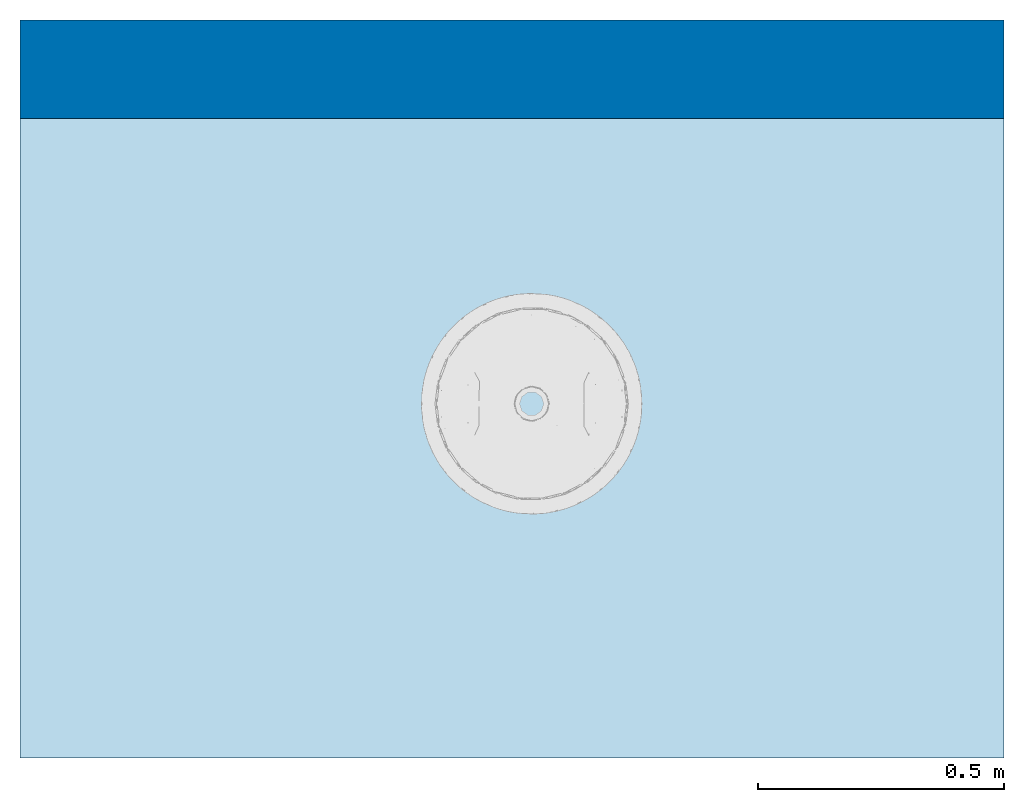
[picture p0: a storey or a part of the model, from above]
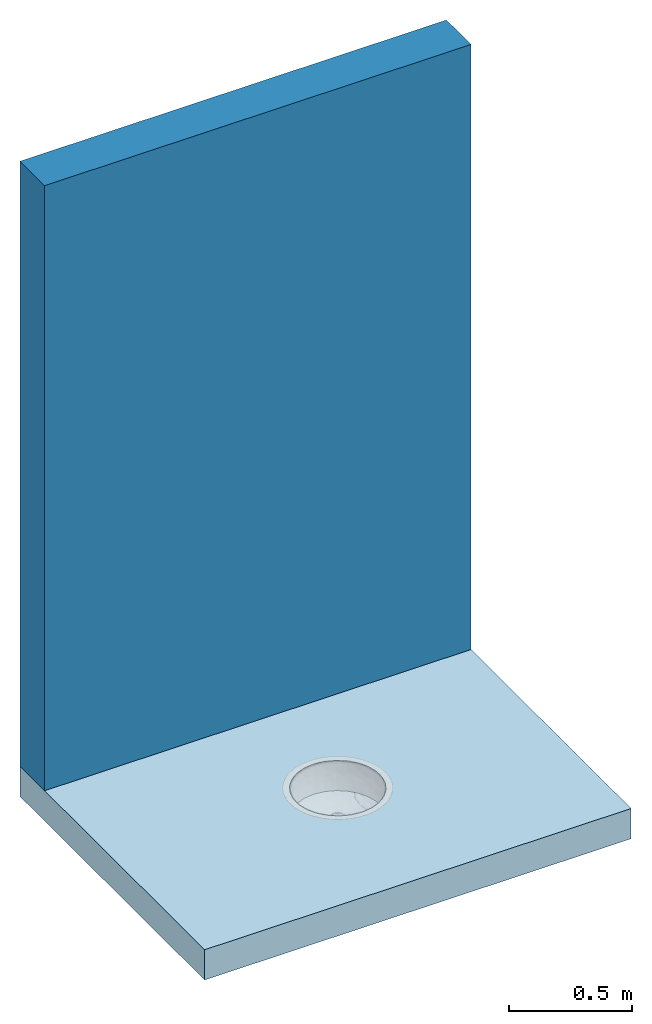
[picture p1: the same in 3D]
Properties of the parts of a building model (IFC2X3)

# File
Description: ViewDefinition [CoordinationView]
File name: 0001
Time: 2017-09-05T11:16:08
Written by: The EXPRESS Data Manager Version 5.02.0100.07 : 28 Aug 2013
Made in: 20160720_1515(x64) - Exporter 17.0.501.0 - Alternate UI 17.13.0.0
Comment: STEP Physical File produced by: The EXPRESS Data Manager Version 5.02.0100.07 : 28 Aug 2013 * Module: EDMstepFileFactory/EDMstandAlone * Creation date: Tue Sep 05 11:16:08 2017 * Host: Polantis_Siza * Database: C:\Users\POLANT~1\AppData\Local\Temp\{5BD8E32A-B00A-4546-B485-FF94F4CEAC49}\ifc * Database version: 5507 * Database creation date: Tue Sep 05 11:16:07 2017 * Schema: IFC2X3 * Model: DataRepository.ifc * Model creation date: Tue Sep 05 11:16:07 2017 * Header model: DataRepository.ifc_HeaderModel * Header model creation date: Tue Sep 05 11:16:07 2017 * EDMuser: sdai-user * EDMgroup: sdai-group * License ID and type: 5605 : Permanent license. Expiry date: * EDMstepFileFactory options: 020000

# IfcProject, 0001
LongName: Project Name; Phase: Project Status

# IfcSite, Default
RefLatitude: 42, 21, 30, 344238; RefLongitude: -71, -3, -35, -194702; RefElevation: 0 mm
Other - Category: Project Information; Client Name: Owner; Project Address: Enter address here; Project Issue Date: Issue Date; Project Name: Project Name; Project Number: 0001; Project Status: Project Status

# IfcBuilding
Pset_BuildingCommon - NumberOfStoreys: 1
Other - Category: Project Information; Client Name: Owner; Project Address: Enter address here; Project Issue Date: Issue Date; Project Name: Project Name; Project Number: 0001; Project Status: Project Status

# IfcBuildingStorey, Level 1
LongName: Level 1; Elevation: 0 mm
Other - Category: Levels; Family Name: Level; Family: Level: 8mm Head; Family and Type: Level: 8mm Head; Type: Level: 8mm Head; Type Id: Level: 8mm Head
Identity Data - Type Name: 8mm Head; Structural: no; Building Story: yes; Name: Level 1
Graphics - Color: 0; Line Pattern: Centre; Line Weight: 1; Symbol: M_Level Head - Circle: M_Level Head - Circle; Symbol at End 1 Default: no; Symbol at End 2 Default: yes
Constraints - Elevation: 0 mm; Elevation Base: Project Base Point
Dimensions - Computation Height: 0 mm

# IfcFlowTerminal: DLB090024-FR, DLB090024-FR:DLB090024-FR:404383
In: Level 1
Material: Stainless Steel
Pset_ManufacturerTypeInformation - Manufacturer: DELABIE
Pset_DistributionFlowElementCommon - Reference: DLB090024-FR
Constraints - Level: Level: Level 1; Elevation: 0 mm; Host: Floor : Generic 150mm; Default Elevation: 1219.2 mm
Dimensions - Area: 0.237805 m2; Volume: 0.000236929 m3; Hauteur: 150 mm; Largeur: 450 mm; Profondeur: 450 mm; Radius: 41.5 mm
Identity Data - Mark: 29; Descriptif: Vasque ronde à encastrer par le dessus ou le dessous. Diamètre intérieur de la vasque : 385 mm. Diamètre de découpe du plan vasque : 400 mm. Inox 304 bactériostatique. Épaisseur Inox : 1 mm. Cuve emboutie d’une seule pièce, sans soudures. Finition anticoupures. Livrée avec bonde 1"1/4. Sans trop-plein. Marquage CE. Conforme à la norme EN 14688. Poids : 1,6 kg.; Description: DELABIE, fabricant français, est le leader européen de l'équipement sanitaire pour les établissements recevant du public. Robinetteries, solutions pour personnes à mobilité réduite, appareils sanitaires, destinés aux écoles, lieux de loisirs, bureaux, hôpitaux, aéroports, ...; Famille de produits: Lavabo; Lien CCTP: http://www.delabie.fr/produits/120490; Lien certification: http://www.delabie.fr/produits/120490; Lien fiche produit: http://www.delabie.fr/produits/120490; Lien notice d'installation: http://www.delabie.fr/produits/120490; Manufacturer: DELABIE; Model: HEMI; OmniClass Number: 23.45.05.14.14; OmniClass Title: Sinks/Lavatories; Polantis code: DLB090024; Type Comments: Vasque à encastrer; Type Name: DLB090024-FR; URL: http://www.delabie.fr
Mechanical - System Classification: Sanitary
Other - Category: Plumbing Fixtures; Family: DLB090024-FR: DLB090024-FR; Family and Type: DLB090024-FR: DLB090024-FR; Schedule Level: Level: Level 1; Type: DLB090024-FR: DLB090024-FR; Type Id: DLB090024-FR: DLB090024-FR; Family Name: DLB090024-FR
Phasing - Phase Created: New Construction
Data - Nom: 120490
Materials and Finishes - DLB090024: Stainless Steel; Finition: Inox 304 poli satiné

# IfcSlab: Floor:Generic 150mm, Floor:Generic 150mm:309211
In: Level 1
PredefinedType: FLOOR; Material: Default Floor 150 mm
Pset_SlabCommon - Reference: Generic 150mm; IsExternal: no; LoadBearing: yes
Constraints - Related to Mass: no; Room Bounding: yes; Height Offset From Level: 0 mm; Level: Level: Level 1
Dimensions - Area: 3 m2; Elevation at Bottom: -150 mm; Elevation at Top: 0 mm; Perimeter: 7000 mm; Thickness: 150 mm; Volume: 0.431917 m3
Other - Category: Floors; Family: Floor: Generic 150mm; Family and Type: Floor: Generic 150mm; Type: Floor: Generic 150mm; Type Id: Floor: Generic 150mm; Family Name: Floor
Phasing - Phase Created: New Construction
Structural - Enable Analytical Model: no; Structural: no
Analytical Properties - Roughness: 3; Absorptance: 0.7
Construction - Default Thickness: 150 mm; Function: Interior
Graphics - Coarse Scale Fill Color: 0
Identity Data - Type Name: Generic 150mm

# IfcWallStandardCase: Basic Wall:Generic - 200mm, Basic Wall:Generic - 200mm:309152
In: Level 1
Type - PredefinedType: STANDARD; Material: Default Wall 200 mm
Type - Analytical Properties - Absorptance: 0.7; Roughness: 3
Type - Construction - Function: Exterior; Width: 200 mm; Wrapping at Inserts: Do not wrap
Type - Graphics - Coarse Scale Fill Color: 0
Type - Identity Data - Type Name: Generic - 200mm
Type - Other - Category: Walls; Family Name: Basic Wall
Constraints - Base Constraint: Level: Level 1; Base Extension Distance: 0 mm; Base is Attached: no; Base Offset: 0 mm; Location Line: Wall Centerline; Related to Mass: no; Room Bounding: yes; Top Extension Distance: 0 mm; Top is Attached: no; Top Offset: 0 mm; Unconnected Height: 3000 mm
Dimensions - Area: 6 m2; Length: 2000 mm; Volume: 1.2 m3
Other - Family: Basic Wall: Generic - 200mm; Family and Type: Basic Wall: Generic - 200mm; Type: Basic Wall: Generic - 200mm; Type Id: Basic Wall: Generic - 200mm
Phasing - Phase Created: New Construction
Structural - Enable Analytical Model: no; Structural: no; Structural Usage: Non-bearing
Pset_WallCommon - Reference: Generic - 200mm; LoadBearing: no; ExtendToStructure: no; IsExternal: yes
